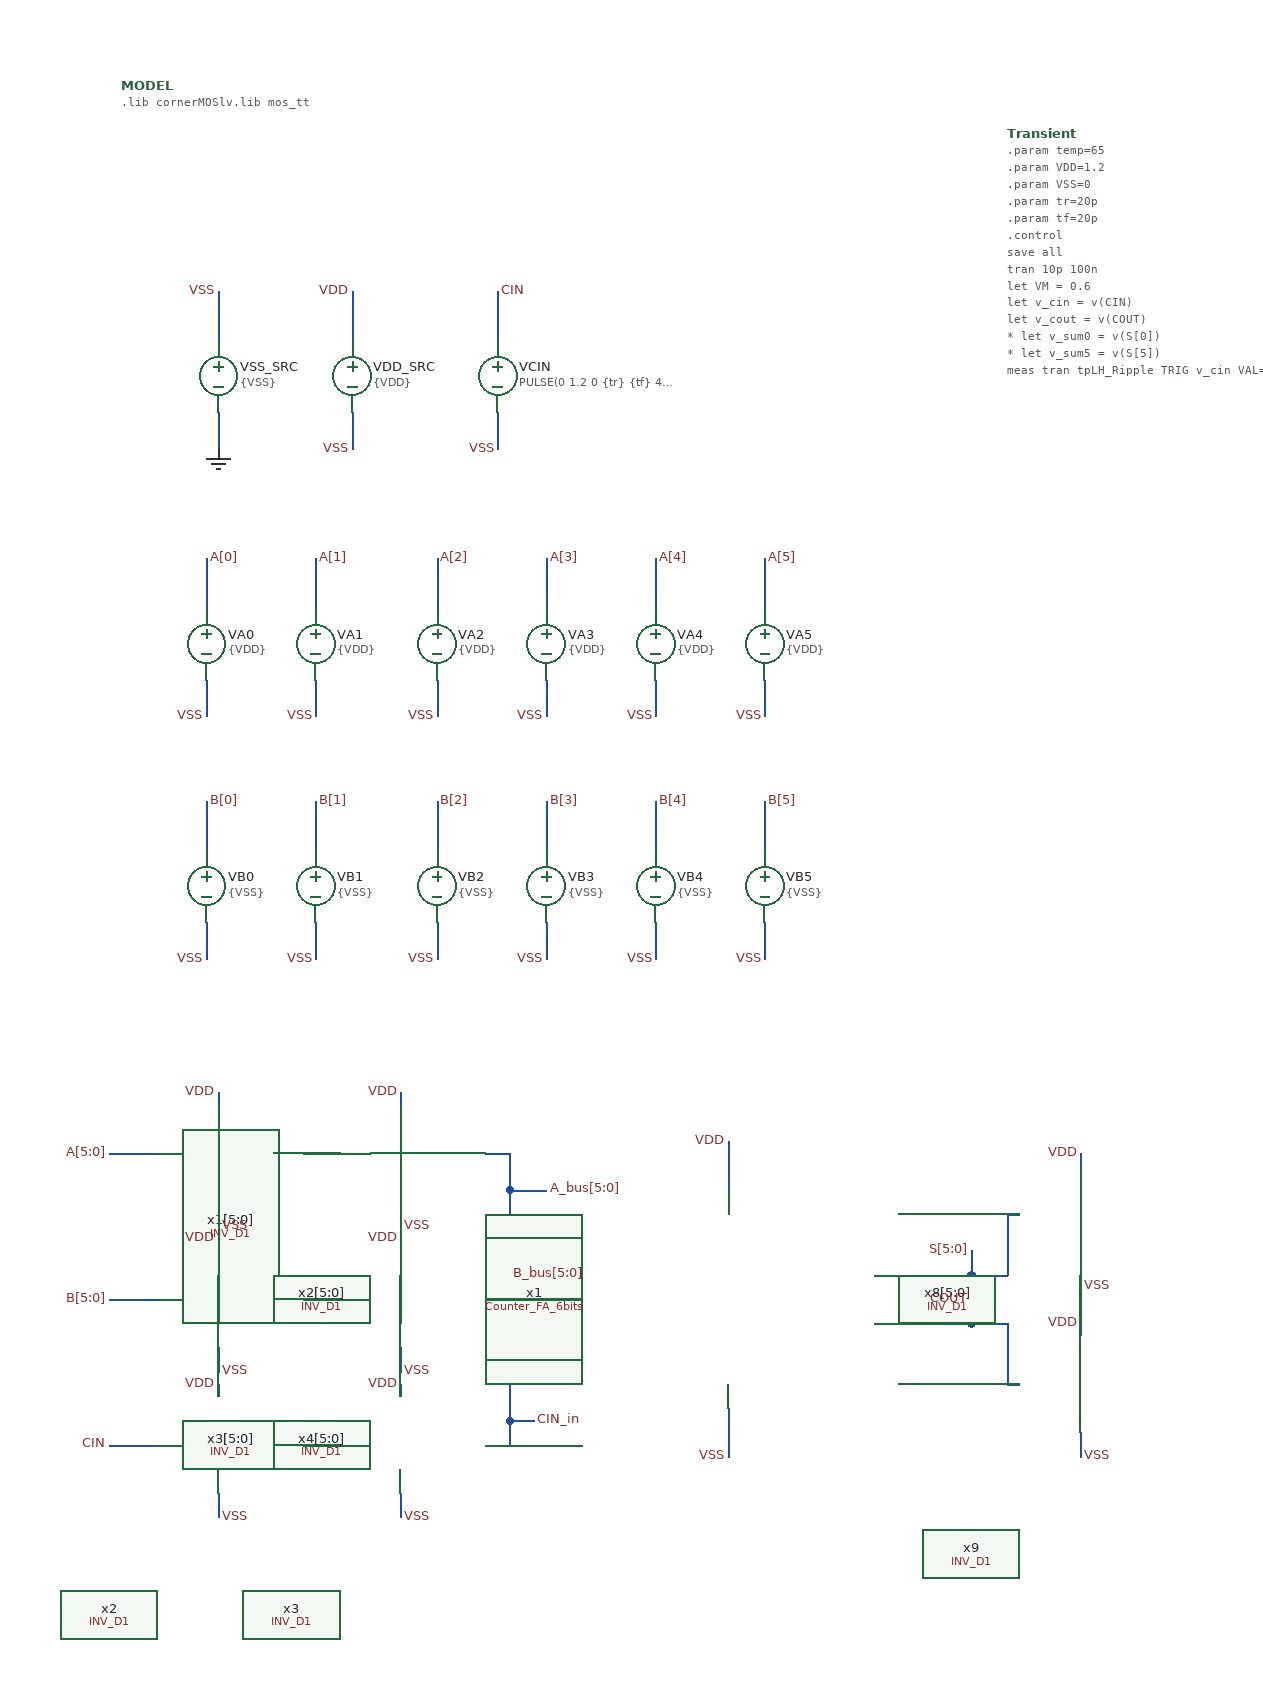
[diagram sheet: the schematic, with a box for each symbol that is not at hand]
v {xschem version=3.4.8RC file_version=1.3}
G {}
K {}
V {}
S {}
F {}
E {}
B 2 2020 -1800 2820 -1400 {flags=graph
y2=1.5
ypos1=0
ypos2=2
divy=5
subdivy=1
unity=1
x1=0
x2=1e-07
divx=5
subdivx=1


dataset=-1
unitx=1
logx=0
logy=0
hilight_wave=0


y1=-0.4
color=7
node=COUT}
B 2 1160 -1810 1960 -1410 {flags=graph
y1=-0.37874992
y2=1.5212501
ypos1=0
ypos2=2
divy=5
subdivy=1
unity=1
x1=0
x2=1e-07
divx=5
subdivx=1


dataset=-1
unitx=1
logx=0
logy=0
hilight_wave=0


color=11
node=CIN}
B 2 1160 -1390 1960 -990 {flags=graph
y1=-0.37874992
y2=1.5212501
ypos1=0
ypos2=2
divy=5
subdivy=1
unity=1
x1=0
x2=1e-07
divx=5
subdivx=1


dataset=-1
unitx=1
logx=0
logy=0
hilight_wave=0


color="11 6 10 12 20 21"
node="A[0]
A[1]
A[2]
A[3]
A[4]
A[5]"}
B 2 2020 -1390 2820 -990 {flags=graph
y1=-0.37874992
y2=1.5212501
ypos1=0
ypos2=2
divy=5
subdivy=1
unity=1
x1=0
x2=1e-07
divx=5
subdivx=1


dataset=-1
unitx=1
logx=0
logy=0
hilight_wave=0


color="11 6 10 12 20 21"
node="B[0]
B[1]
B[2]
B[3]
B[4]
B[5]"}
B 2 1160 -970 1960 -570 {flags=graph
y1=-0.37874992
y2=1.5212501
ypos1=0
ypos2=2
divy=5
subdivy=1
unity=1
x1=0
x2=1e-07
divx=5
subdivx=1


dataset=-1
unitx=1
logx=0
logy=0
hilight_wave=0


color="11 6 10 12 20 21"
node="S[0]
S[1]
S[2]
S[3]
S[4]
S[5]"}
N 650 -970 650 -930 {lab=VDD}
N 650 -750 650 -710 {lab=VSS}
N 850 -820 880 -820 {lab=COUT}
N 940 -960 940 -950 {lab=VDD}
N 940 -870 940 -850 {lab=VSS}
N 940 -820 940 -810 {lab=VDD}
N 940 -730 940 -710 {lab=VSS}
N 880 -820 880 -770 {lab=COUT}
N 880 -770 890 -770 {lab=COUT}
N 880 -910 890 -910 {lab=S[5:0]}
N 230 -1570 230 -1540 {lab=GND}
N 230 -1670 230 -1630 {lab=VSS}
N 220 -1350 220 -1320 {lab=VSS}
N 220 -1450 220 -1410 {lab=A[0]}
N 340 -1570 340 -1540 {lab=VSS}
N 340 -1670 340 -1630 {lab=VDD}
N 220 -1150 220 -1120 {lab=VSS}
N 220 -1250 220 -1210 {lab=B[0]}
N 460 -1570 460 -1540 {lab=VSS}
N 460 -1670 460 -1630 {lab=CIN}
N 310 -1150 310 -1120 {lab=VSS}
N 310 -1250 310 -1210 {lab=B[1]}
N 410 -1150 410 -1120 {lab=VSS}
N 410 -1250 410 -1210 {lab=B[2]}
N 500 -1150 500 -1120 {lab=VSS}
N 500 -1250 500 -1210 {lab=B[3]}
N 590 -1150 590 -1120 {lab=VSS}
N 590 -1250 590 -1210 {lab=B[4]}
N 680 -1150 680 -1120 {lab=VSS}
N 680 -1250 680 -1210 {lab=B[5]}
N 310 -1350 310 -1320 {lab=VSS}
N 310 -1450 310 -1410 {lab=A[1]}
N 410 -1350 410 -1320 {lab=VSS}
N 410 -1450 410 -1410 {lab=A[2]}
N 500 -1350 500 -1320 {lab=VSS}
N 500 -1450 500 -1410 {lab=A[3]}
N 590 -1350 590 -1320 {lab=VSS}
N 590 -1450 590 -1410 {lab=A[4]}
N 680 -1350 680 -1320 {lab=VSS}
N 680 -1450 680 -1410 {lab=A[5]}
N 850 -860 880 -860 {lab=S[5:0]}
N 880 -910 880 -860 {lab=S[5:0]}
N 230 -1010 230 -1000 {lab=VDD}
N 230 -920 230 -900 {lab=VSS}
N 230 -770 230 -760 {lab=VDD}
N 230 -680 230 -660 {lab=VSS}
N 380 -1010 380 -1000 {lab=VDD}
N 380 -770 380 -760 {lab=VDD}
N 380 -680 380 -660 {lab=VSS}
N 230 -890 230 -880 {lab=VDD}
N 230 -800 230 -780 {lab=VSS}
N 380 -890 380 -880 {lab=VDD}
N 380 -800 380 -780 {lab=VSS}
N 380 -920 380 -900 {lab=VSS}
N 140 -960 180 -960 {lab=A[5:0]}
N 300 -960 330 -960 {lab=#net1}
N 450 -960 470 -960 {lab=A_bus[5:0]}
N 470 -930 470 -890 {lab=A_bus[5:0]}
N 470 -890 530 -890 {lab=A_bus[5:0]}
N 470 -840 530 -840 {lab=B_bus[5:0]}
N 300 -840 330 -840 {lab=#net2}
N 140 -840 180 -840 {lab=B[5:0]}
N 140 -720 180 -720 {lab=CIN}
N 300 -720 330 -720 {lab=#net3}
N 450 -720 470 -720 {lab=CIN_in}
N 470 -740 470 -720 {lab=CIN_in}
N 470 -790 530 -790 {lab=CIN_in}
N 470 -930 500 -930 {lab=A_bus[5:0]}
N 470 -960 470 -930 {lab=A_bus[5:0]}
N 470 -860 470 -840 {lab=B_bus[5:0]}
N 450 -840 470 -840 {lab=B_bus[5:0]}
N 470 -740 490 -740 {lab=CIN_in}
N 470 -790 470 -740 {lab=CIN_in}
N 850 -880 850 -860 {lab=S[5:0]}
N 770 -860 850 -860 {lab=S[5:0]}
N 850 -840 850 -820 {lab=COUT}
N 770 -820 850 -820 {lab=COUT}
C {devices/launcher.sym} 545 -1725 0 0 {name=h5
descr="load waves Ctrl + left click" 
tclcommand="xschem raw_read $netlist_dir/tb_Counter_FA_6bits_v2.raw tran"
}
C {devices/launcher.sym} 545 -1805 0 0 {name=h1
descr="simulate" 
tclcommand="xschem save; xschem netlist; xschem simulate"
}
C {devices/code_shown.sym} 150 -1840 0 0 {name=MODEL only_toplevel=true
format="tcleval( @value )"
value="
.lib cornerMOSlv.lib mos_tt
"}
C {lab_wire.sym} 650 -970 0 0 {name=p17 sig_type=std_logic lab=VDD}
C {lab_wire.sym} 650 -710 0 0 {name=p21 sig_type=std_logic lab=VSS}
C {Counter_FA_6bits.sym} 510 -750 0 0 {name=x1}
C {lab_wire.sym} 140 -840 0 0 {name=p9 sig_type=std_logic lab=B[5:0]
}
C {lab_wire.sym} 140 -960 0 0 {name=p10 sig_type=std_logic lab=A[5:0]
}
C {lab_wire.sym} 140 -720 0 0 {name=p29 sig_type=std_logic lab=CIN
}
C {INV_D1.sym} 850 -770 0 0 {name=x8[5:0]}
C {lab_wire.sym} 940 -960 0 0 {name=p27 sig_type=std_logic lab=VDD}
C {lab_wire.sym} 940 -850 0 1 {name=p28 sig_type=std_logic lab=VSS}
C {INV_D1.sym} 850 -630 0 0 {name=x9}
C {lab_wire.sym} 940 -820 0 0 {name=p6 sig_type=std_logic lab=VDD}
C {lab_wire.sym} 940 -710 0 1 {name=p30 sig_type=std_logic lab=VSS}
C {code.sym} 880 -1800 0 0 {name=Transient only_toplevel=false value="

.param temp=65
.param VDD=1.2
.param VSS=0
.param tr=20p
.param tf=20p

.control
save all
tran 10p 100n

let VM = 0.6
let v_cin  = v(CIN)
let v_cout = v(COUT) 
* let v_sum0 = v(S[0])
* let v_sum5 = v(S[5])

meas tran tpLH_Ripple TRIG v_cin VAL=VM RISE=1 TD=10n TARG v_cout VAL=VM RISE=1 TD=10n
meas tran tpHL_Ripple TRIG v_cin VAL=VM FALL=1 TD=50n TARG v_cout VAL=VM FALL=1 TD=50n

let tp_Ripple = (tpLH_Ripple + tpHL_Ripple)/2
print tp_Ripple

* meas tran tp_S0 TRIG v_cin VAL=VM RISE=1 TD=10n TARG v_sum0 VAL=VM CROSS=1 TD=10n
* meas tran tp_S5 TRIG v_cin VAL=VM RISE=1 TD=10n TARG v_sum5 VAL=VM CROSS=1 TD=10n

* let delay_skew = tp_S5 - tp_S0
* print delay_skew

let i_vdd = i(VDD_SRC)
meas tran i_avg AVG i_vdd FROM=0n TO=100n

* Graficar
* plot v(CIN) v(S[0])+2 v(S[2])+4 v(S[4])+6 v(COUT)+8 title Efecto Ripple Carry

write tb_Counter_FA_6bits_v2.raw
set appendwrite

.endc
"}
C {vsource.sym} 230 -1600 0 0 {name=VSS_SRC value=\{VSS\} savecurrent=false}
C {gnd.sym} 230 -1540 0 0 {name=l1 lab=GND}
C {lab_wire.sym} 230 -1670 0 0 {name=p1 sig_type=std_logic lab=VSS}
C {lab_wire.sym} 220 -1320 0 0 {name=p5 sig_type=std_logic lab=VSS}
C {lab_wire.sym} 220 -1450 0 1 {name=p8 sig_type=std_logic lab=A[0]
}
C {vsource.sym} 340 -1600 0 0 {name=VDD_SRC value=\{VDD\} savecurrent=false}
C {lab_wire.sym} 340 -1540 0 0 {name=p12 sig_type=std_logic lab=VSS}
C {lab_wire.sym} 340 -1670 0 0 {name=p13 sig_type=std_logic lab=VDD}
C {lab_wire.sym} 220 -1120 0 0 {name=p4 sig_type=std_logic lab=VSS}
C {lab_wire.sym} 220 -1250 0 1 {name=p7 sig_type=std_logic lab=B[0]
}
C {vsource.sym} 220 -1180 0 0 {name=VB0 value="\{VSS\}" savecurrent=false}
C {lab_wire.sym} 460 -1540 0 0 {name=p31 sig_type=std_logic lab=VSS}
C {vsource.sym} 460 -1600 0 0 {name=VCIN value="PULSE(0 1.2 0 \{tr\} \{tf\} 40n 100n)" savecurrent=false}
C {lab_wire.sym} 460 -1670 0 1 {name=p32 sig_type=std_logic lab=CIN
}
C {lab_wire.sym} 310 -1120 0 0 {name=p33 sig_type=std_logic lab=VSS}
C {lab_wire.sym} 310 -1250 0 1 {name=p34 sig_type=std_logic lab=B[1]
}
C {vsource.sym} 310 -1180 0 0 {name=VB1 value="\{VSS\}" savecurrent=false}
C {lab_wire.sym} 410 -1120 0 0 {name=p35 sig_type=std_logic lab=VSS}
C {lab_wire.sym} 410 -1250 0 1 {name=p36 sig_type=std_logic lab=B[2]
}
C {vsource.sym} 410 -1180 0 0 {name=VB2 value="\{VSS\}" savecurrent=false}
C {lab_wire.sym} 500 -1120 0 0 {name=p37 sig_type=std_logic lab=VSS}
C {lab_wire.sym} 500 -1250 0 1 {name=p38 sig_type=std_logic lab=B[3]
}
C {vsource.sym} 500 -1180 0 0 {name=VB3 value="\{VSS\}" savecurrent=false}
C {lab_wire.sym} 590 -1120 0 0 {name=p39 sig_type=std_logic lab=VSS}
C {lab_wire.sym} 590 -1250 0 1 {name=p40 sig_type=std_logic lab=B[4]
}
C {vsource.sym} 590 -1180 0 0 {name=VB4 value="\{VSS\}" savecurrent=false}
C {lab_wire.sym} 680 -1120 0 0 {name=p41 sig_type=std_logic lab=VSS}
C {lab_wire.sym} 680 -1250 0 1 {name=p42 sig_type=std_logic lab=B[5]
}
C {vsource.sym} 680 -1180 0 0 {name=VB5 value="\{VSS\}" savecurrent=false}
C {vsource.sym} 220 -1380 0 0 {name=VA0 value=\{VDD\} savecurrent=false}
C {lab_wire.sym} 310 -1320 0 0 {name=p43 sig_type=std_logic lab=VSS}
C {lab_wire.sym} 310 -1450 0 1 {name=p44 sig_type=std_logic lab=A[1]
}
C {vsource.sym} 310 -1380 0 0 {name=VA1 value=\{VDD\} savecurrent=false}
C {lab_wire.sym} 410 -1320 0 0 {name=p45 sig_type=std_logic lab=VSS}
C {lab_wire.sym} 410 -1450 0 1 {name=p46 sig_type=std_logic lab=A[2]
}
C {vsource.sym} 410 -1380 0 0 {name=VA2 value=\{VDD\} savecurrent=false}
C {lab_wire.sym} 500 -1320 0 0 {name=p47 sig_type=std_logic lab=VSS}
C {lab_wire.sym} 500 -1450 0 1 {name=p48 sig_type=std_logic lab=A[3]
}
C {vsource.sym} 500 -1380 0 0 {name=VA3 value=\{VDD\} savecurrent=false}
C {lab_wire.sym} 590 -1320 0 0 {name=p49 sig_type=std_logic lab=VSS}
C {lab_wire.sym} 590 -1450 0 1 {name=p50 sig_type=std_logic lab=A[4]
}
C {vsource.sym} 590 -1380 0 0 {name=VA4 value=\{VDD\} savecurrent=false}
C {lab_wire.sym} 680 -1320 0 0 {name=p51 sig_type=std_logic lab=VSS}
C {lab_wire.sym} 680 -1450 0 1 {name=p52 sig_type=std_logic lab=A[5]
}
C {vsource.sym} 680 -1380 0 0 {name=VA5 value=\{VDD\} savecurrent=false}
C {lab_wire.sym} 850 -880 0 0 {name=p2 sig_type=std_logic lab=S[5:0]}
C {lab_wire.sym} 850 -840 0 0 {name=p3 sig_type=std_logic lab=COUT}
C {INV_D1.sym} 140 -820 0 0 {name=x1[5:0]}
C {lab_wire.sym} 230 -1010 0 0 {name=p11 sig_type=std_logic lab=VDD}
C {lab_wire.sym} 230 -900 0 1 {name=p14 sig_type=std_logic lab=VSS}
C {INV_D1.sym} 140 -580 0 0 {name=x2}
C {lab_wire.sym} 230 -770 0 0 {name=p15 sig_type=std_logic lab=VDD}
C {lab_wire.sym} 230 -660 0 1 {name=p16 sig_type=std_logic lab=VSS}
C {INV_D1.sym} 290 -820 0 0 {name=x2[5:0]}
C {lab_wire.sym} 380 -1010 0 0 {name=p18 sig_type=std_logic lab=VDD}
C {lab_wire.sym} 380 -900 0 1 {name=p19 sig_type=std_logic lab=VSS}
C {INV_D1.sym} 290 -580 0 0 {name=x3}
C {lab_wire.sym} 380 -770 0 0 {name=p20 sig_type=std_logic lab=VDD}
C {lab_wire.sym} 380 -660 0 1 {name=p22 sig_type=std_logic lab=VSS}
C {INV_D1.sym} 140 -700 0 0 {name=x3[5:0]}
C {lab_wire.sym} 230 -890 0 0 {name=p23 sig_type=std_logic lab=VDD}
C {lab_wire.sym} 230 -780 0 1 {name=p24 sig_type=std_logic lab=VSS}
C {INV_D1.sym} 290 -700 0 0 {name=x4[5:0]}
C {lab_wire.sym} 380 -890 0 0 {name=p25 sig_type=std_logic lab=VDD}
C {lab_wire.sym} 380 -780 0 1 {name=p26 sig_type=std_logic lab=VSS}
C {lab_wire.sym} 500 -930 0 1 {name=p53 sig_type=std_logic lab=A_bus[5:0]}
C {lab_wire.sym} 470 -860 0 1 {name=p54 sig_type=std_logic lab=B_bus[5:0]}
C {lab_wire.sym} 490 -740 0 1 {name=p55 sig_type=std_logic lab=CIN_in}
